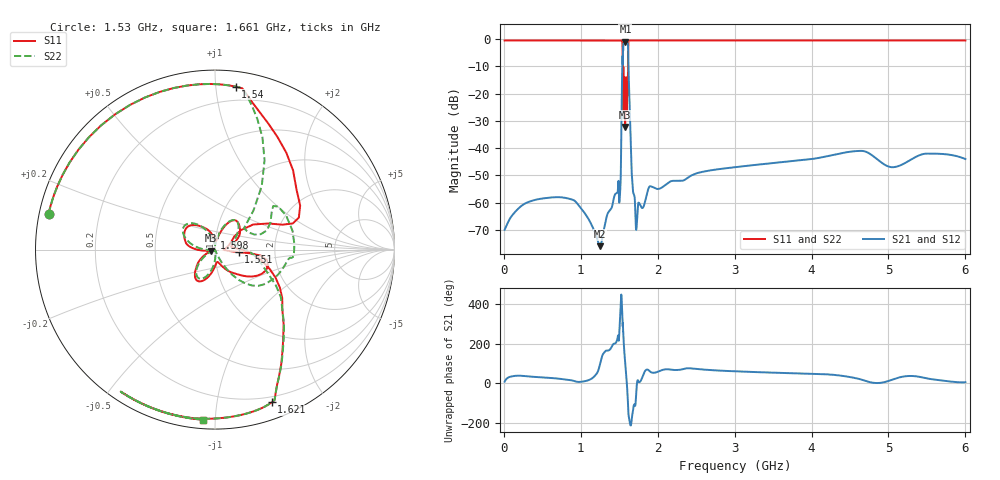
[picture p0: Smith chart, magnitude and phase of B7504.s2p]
! Project 16: GNSS L1 + L2/L5 active antenna front end (RFMW-ANT)
! Generated by Scripts/simulate.py from Scripts/ds_data.py; format GHz / RI, Z0 = 50 ohm
! ESTIMATED from Qualcomm RF360 B7504 (B39162B7504L210) data sheet v2.2, 4 Nov 2019: |S21| digitized from Fig. 4 anchored to the p.7
! attenuation table; |S11|,|S22| from VSWR Fig. 5/6 (1540-1620 MHz), reflective outside;
! phase = minimum-phase reconstruction; arg S11 = arg S22 = arg S21 + 90 deg.
! NOT measured data. Replace with the RF360 measured .s2p when available.
# GHz S RI R 50.0
!freq ReS11 ImS11 ReS21 ImS21 ReS12 ImS12 ReS22 ImS22
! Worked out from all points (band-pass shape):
!   11981 points, 10 MHz to 6 GHz, reference 50 ohm
!   highest |S21| = -0.85 dB at 1.58 GHz (marker M1); lowest = -76.0 dB at 1.25 GHz (marker M2)
!   |S21| within 3 dB of the highest: 1.548433 GHz to 1.550303 GHz (1.87 MHz wide, 0.121 % of centre); 1.552 GHz to 1.616 GHz (64.27 MHz wide, 4.06 % of centre)
!   lowest |S11| = -32.3 dB at 1.577 GHz (marker M3), VSWR 1.05, Z = 47.7 - j0.635 ohm
!   |S11| at or under -10 dB: 1.547 GHz to 1.614 GHz (67.34 MHz wide, 4.26 % of centre)
!   |S22| runs from - to -0.4 dB; largest |S21 - S12| = 0
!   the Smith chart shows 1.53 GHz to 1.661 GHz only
!   S11 on the Smith chart (normalised r, x): 1.53 GHz: 0.03, +0.11; 1.54 GHz: 0.10, +1.13; 1.551 GHz: 1.30, -0.04; 1.598 GHz: 0.98, +0.13; 1.621 GHz: 0.15, -1.43; 1.661 GHz: 0.05, -0.93
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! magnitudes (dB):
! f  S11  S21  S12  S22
! 10 MHz  -0.4  -70.0  -70.0  -0.4
! 405 MHz  -0.4  -59.0  -59.0  -0.4
! 1.008 GHz  -0.4  -62.3  -62.3  -0.4
! 1.25 GHz  -0.4  -76.0  -76.0  -0.4
! 1.492 GHz  -0.4  -52.8  -52.8  -0.4
! 1.53 GHz  -0.5  -25.1  -25.1  -0.5
! 1.54 GHz  -0.8  -11.5  -11.5  -0.8
! 1.551 GHz  -17.5  -4.2  -4.2  -7.3
! 1.577 GHz  -32.3  -0.9  -0.9  -
! 1.58 GHz  -20.7  -0.9  -0.9  -26.4
! 1.598 GHz  -23.9  -1.0  -1.0  -30.5
! 1.621 GHz  -0.8  -10.6  -10.6  -0.8
! 1.661 GHz  -0.4  -48.5  -48.5  -0.4
! 1.698 GHz  -0.4  -57.7  -57.7  -0.4
! 1.731 GHz  -0.4  -67.0  -67.0  -0.4
! 1.896 GHz  -0.4  -54.0  -54.0  -0.4
! 2.007 GHz  -0.4  -55.0  -55.0  -0.4
! 3.005 GHz  -0.4  -47.0  -47.0  -0.4
! 4.003 GHz  -0.4  -44.0  -44.0  -0.4
! 4.66 GHz  -0.4  -41.0  -41.0  -0.4
! 5.002 GHz  -0.4  -46.8  -46.8  -0.4
! 6 GHz  -0.4  -44.0  -44.0  -0.4
